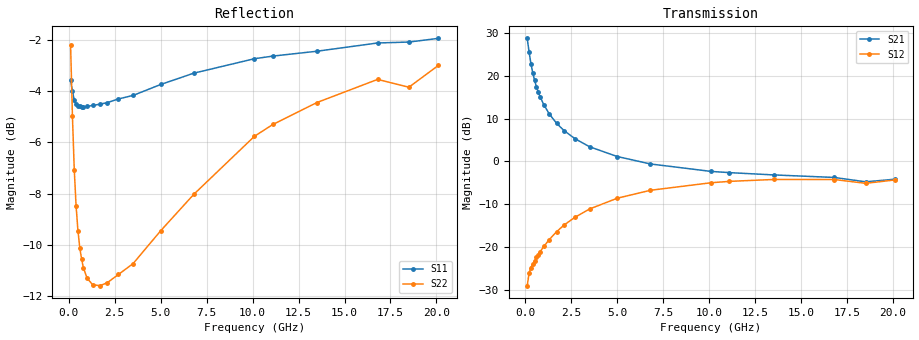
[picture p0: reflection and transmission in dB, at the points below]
!  Infineon Technologies AG
! BFR380L3 , PF131585-7, No.6, Th 09.10.01, soldered on pcb-board, measured with PP GSG850
!  Vce=0.5 V,  Ic=12.5 mA
! Common Emitter S-Parameters:  15. November 2001
#  GHz  S  MA  R  50
! f  S11  S21  S12  S22
! GHz  Mag  Ang  Mag  Ang  Mag  Ang  Mag  Ang
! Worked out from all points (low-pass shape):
!   201 points, 100 MHz to 20.1 GHz, reference 50 ohm
!   highest |S21| = 28.74 dB at 100 MHz (marker M1); lowest = -4.8 dB at 18.5 GHz (marker M2)
!   |S21| within 3 dB of the highest: start of sweep to 193.3 MHz
!   lowest |S11| = -4.6 dB at 800 MHz (marker M3), VSWR 3.86, Z = 13 - j4.08 ohm
!   |S11| at or under -10 dB: nowhere
!   |S22| runs from -11.6 to -2.2 dB; largest |S21 - S12| = 27
!   S11 on the Smith chart (normalised r, x): 100 MHz: 0.58, -1.27; 300 MHz: 0.29, -0.42; 1.3 GHz: 0.26, +0.04; 5 GHz: 0.28, +0.56; 11.1 GHz: 0.43, +1.32; 20.1 GHz: 0.93, +2.59
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0.1  0.6627 -69.5  27.34 141.3  0.03514 58.2  0.7785 -48.1
0.2  0.6308 -109.2  18.88 120.4  0.04948 48.1  0.5655 -77.5
0.3  0.607 -131.2  13.85 109.4  0.05718 45.3  0.4437 -95.9
0.4  0.5958 -144.4  10.81 102.4  0.06325 45.4  0.3765 -109.2
0.5  0.592 -153.6  8.825 97.4  0.06897 46.9  0.3369 -119.5
0.6  0.59 -160.3  7.443 93.6  0.07509 48.2  0.3121 -127.6
0.7  0.5889 -165.5  6.439 90.2  0.08129 49.9  0.2963 -134.3
0.8  0.5888 -170.0  5.669 87.4  0.08763 51.2  0.2848 -139.8
1  0.5896 -177.0  4.584 82.5  0.101 53.4  0.2719 -148.4
1.3  0.5921 174.8  3.57 76.3  0.1218 55.4  0.264 -157.8
1.7  0.5956 166.2  2.772 69.1  0.1506 56.0  0.2629 -166.6
2.1  0.5997 158.8  2.286 62.6  0.1796 55.4  0.2665 -173.1
2.7  0.6098 148.8  1.834 53.8  0.2219 53.2  0.2765 178.7
3.5  0.6195 137.2  1.475 43.1  0.2775 48.8  0.2904 170.2
5  0.6508 118.7  1.136 26.5  0.3702 39.0  0.3367 155.2
6.8  0.6848 100.4  0.9305 11.1  0.4581 26.7  0.3967 138.3
10.1  0.7309 76.2  0.7613 -8.5  0.5612 6.0  0.5153 113.0
11.1  0.7396 70.5  0.7368 -13.3  0.5825 -0.0  0.5435 105.8
13.5  0.756 59.5  0.6929 -23.7  0.6128 -13.2  0.6 89.9
16.8  0.7846 47.4  0.6472 -34.7  0.6122 -27.8  0.6659 71.8
18.5  0.7879 45.4  0.5753 -42.1  0.5528 -35.8  0.6428 67.2
20.1  0.8011 38.2  0.6173 -45.5  0.6046 -40.5  0.709 57.4
